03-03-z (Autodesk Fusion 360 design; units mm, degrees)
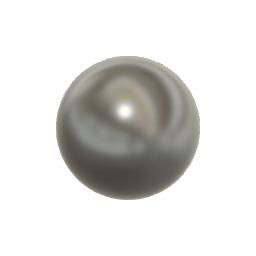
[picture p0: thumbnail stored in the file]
sphere_primitive "球プリミティブ" Diameter 50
